VERSION 5.7 ;
  NOWIREEXTENSIONATPIN ON ;
  DIVIDERCHAR "/" ;
  BUSBITCHARS "[]" ;
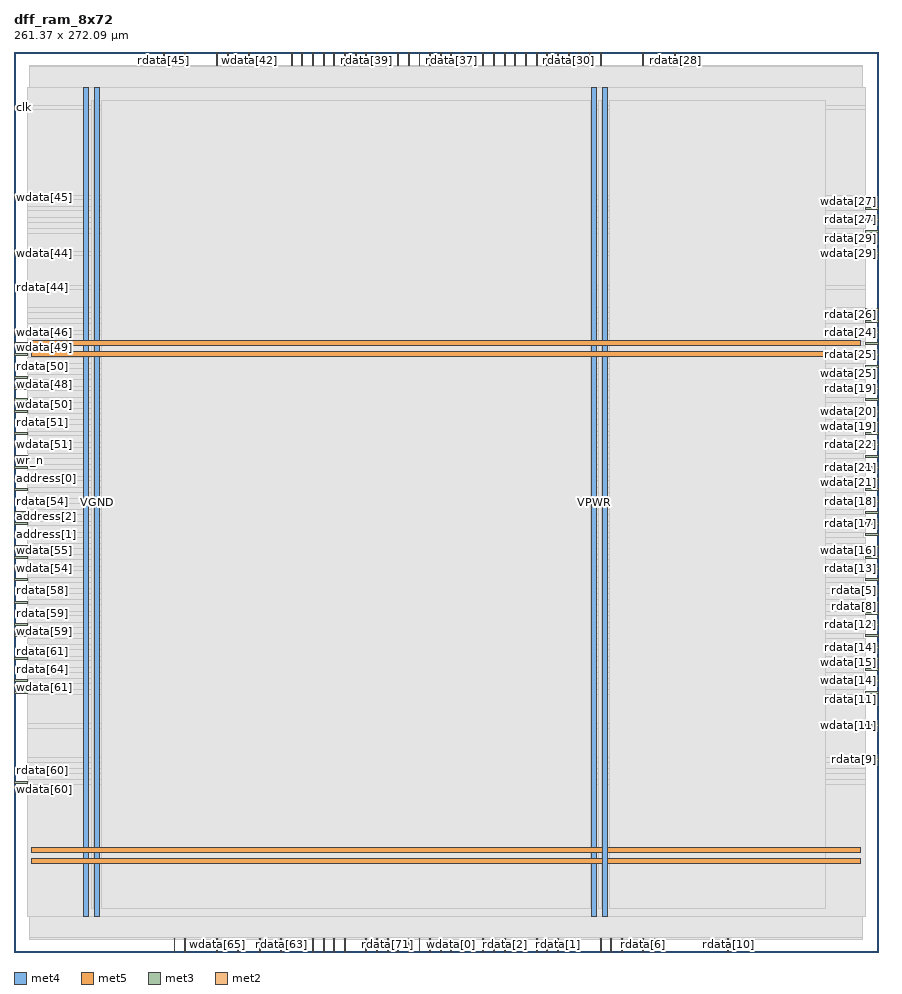
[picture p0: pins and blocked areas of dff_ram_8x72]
MACRO dff_ram_8x72
  CLASS BLOCK ;
  FOREIGN dff_ram_8x72 ;
  ORIGIN 0.000 0.000 ;
  SIZE 261.370 BY 272.090 ;
  PIN VGND
    DIRECTION INOUT ;
    USE GROUND ;
    PORT
      LAYER met4 ;
        RECT 24.340 10.640 25.940 261.360 ;
    END
    PORT
      LAYER met4 ;
        RECT 177.940 10.640 179.540 261.360 ;
    END
    PORT
      LAYER met5 ;
        RECT 5.280 30.030 256.000 31.630 ;
    END
    PORT
      LAYER met5 ;
        RECT 5.280 183.210 256.000 184.810 ;
    END
  END VGND
  PIN VPWR
    DIRECTION INOUT ;
    USE POWER ;
    PORT
      LAYER met4 ;
        RECT 21.040 10.640 22.640 261.360 ;
    END
    PORT
      LAYER met4 ;
        RECT 174.640 10.640 176.240 261.360 ;
    END
    PORT
      LAYER met5 ;
        RECT 5.280 26.730 256.000 28.330 ;
    END
    PORT
      LAYER met5 ;
        RECT 5.280 179.910 256.000 181.510 ;
    END
  END VPWR
  PIN address[0]
    DIRECTION INPUT ;
    USE SIGNAL ;
    ANTENNAGATEAREA 0.126000 ;
    PORT
      LAYER met3 ;
        RECT 0.000 142.840 4.000 143.440 ;
    END
  END address[0]
  PIN address[1]
    DIRECTION INPUT ;
    USE SIGNAL ;
    ANTENNAGATEAREA 0.126000 ;
    PORT
      LAYER met3 ;
        RECT 0.000 125.840 4.000 126.440 ;
    END
  END address[1]
  PIN address[2]
    DIRECTION INPUT ;
    USE SIGNAL ;
    ANTENNAGATEAREA 0.213000 ;
    PORT
      LAYER met3 ;
        RECT 0.000 129.240 4.000 129.840 ;
    END
  END address[2]
  PIN clk
    DIRECTION INPUT ;
    USE SIGNAL ;
    ANTENNAGATEAREA 0.852000 ;
    PORT
      LAYER met3 ;
        RECT 0.000 255.040 4.000 255.640 ;
    END
  END clk
  PIN rdata[0]
    DIRECTION OUTPUT TRISTATE ;
    USE SIGNAL ;
    ANTENNADIFFAREA 0.795200 ;
    PORT
      LAYER met2 ;
        RECT 144.990 0.000 145.270 4.000 ;
    END
  END rdata[0]
  PIN rdata[10]
    DIRECTION OUTPUT TRISTATE ;
    USE SIGNAL ;
    ANTENNADIFFAREA 0.795200 ;
    PORT
      LAYER met2 ;
        RECT 215.830 0.000 216.110 4.000 ;
    END
  END rdata[10]
  PIN rdata[11]
    DIRECTION OUTPUT TRISTATE ;
    USE SIGNAL ;
    ANTENNADIFFAREA 0.795200 ;
    PORT
      LAYER met3 ;
        RECT 257.370 78.240 261.370 78.840 ;
    END
  END rdata[11]
  PIN rdata[12]
    DIRECTION OUTPUT TRISTATE ;
    USE SIGNAL ;
    ANTENNADIFFAREA 0.795200 ;
    PORT
      LAYER met3 ;
        RECT 257.370 98.640 261.370 99.240 ;
    END
  END rdata[12]
  PIN rdata[13]
    DIRECTION OUTPUT TRISTATE ;
    USE SIGNAL ;
    ANTENNADIFFAREA 0.795200 ;
    PORT
      LAYER met3 ;
        RECT 257.370 115.640 261.370 116.240 ;
    END
  END rdata[13]
  PIN rdata[14]
    DIRECTION OUTPUT TRISTATE ;
    USE SIGNAL ;
    ANTENNADIFFAREA 0.795200 ;
    PORT
      LAYER met3 ;
        RECT 257.370 91.840 261.370 92.440 ;
    END
  END rdata[14]
  PIN rdata[15]
    DIRECTION OUTPUT TRISTATE ;
    USE SIGNAL ;
    ANTENNADIFFAREA 0.445500 ;
    PORT
      LAYER met3 ;
        RECT 257.370 95.240 261.370 95.840 ;
    END
  END rdata[15]
  PIN rdata[16]
    DIRECTION OUTPUT TRISTATE ;
    USE SIGNAL ;
    ANTENNADIFFAREA 0.445500 ;
    PORT
      LAYER met3 ;
        RECT 257.370 122.440 261.370 123.040 ;
    END
  END rdata[16]
  PIN rdata[17]
    DIRECTION OUTPUT TRISTATE ;
    USE SIGNAL ;
    ANTENNADIFFAREA 0.445500 ;
    PORT
      LAYER met3 ;
        RECT 257.370 129.240 261.370 129.840 ;
    END
  END rdata[17]
  PIN rdata[18]
    DIRECTION OUTPUT TRISTATE ;
    USE SIGNAL ;
    ANTENNADIFFAREA 0.795200 ;
    PORT
      LAYER met3 ;
        RECT 257.370 136.040 261.370 136.640 ;
    END
  END rdata[18]
  PIN rdata[19]
    DIRECTION OUTPUT TRISTATE ;
    USE SIGNAL ;
    ANTENNADIFFAREA 0.795200 ;
    PORT
      LAYER met3 ;
        RECT 257.370 170.040 261.370 170.640 ;
    END
  END rdata[19]
  PIN rdata[1]
    DIRECTION OUTPUT TRISTATE ;
    USE SIGNAL ;
    ANTENNADIFFAREA 0.795200 ;
    PORT
      LAYER met2 ;
        RECT 164.310 0.000 164.590 4.000 ;
    END
  END rdata[1]
  PIN rdata[20]
    DIRECTION OUTPUT TRISTATE ;
    USE SIGNAL ;
    ANTENNADIFFAREA 0.445500 ;
    PORT
      LAYER met3 ;
        RECT 257.370 166.640 261.370 167.240 ;
    END
  END rdata[20]
  PIN rdata[21]
    DIRECTION OUTPUT TRISTATE ;
    USE SIGNAL ;
    ANTENNADIFFAREA 0.795200 ;
    PORT
      LAYER met3 ;
        RECT 257.370 146.240 261.370 146.840 ;
    END
  END rdata[21]
  PIN rdata[22]
    DIRECTION OUTPUT TRISTATE ;
    USE SIGNAL ;
    ANTENNADIFFAREA 0.795200 ;
    PORT
      LAYER met3 ;
        RECT 257.370 153.040 261.370 153.640 ;
    END
  END rdata[22]
  PIN rdata[23]
    DIRECTION OUTPUT TRISTATE ;
    USE SIGNAL ;
    ANTENNADIFFAREA 0.795200 ;
    PORT
      LAYER met3 ;
        RECT 257.370 149.640 261.370 150.240 ;
    END
  END rdata[23]
  PIN rdata[24]
    DIRECTION OUTPUT TRISTATE ;
    USE SIGNAL ;
    ANTENNADIFFAREA 0.795200 ;
    PORT
      LAYER met3 ;
        RECT 257.370 187.040 261.370 187.640 ;
    END
  END rdata[24]
  PIN rdata[25]
    DIRECTION OUTPUT TRISTATE ;
    USE SIGNAL ;
    ANTENNADIFFAREA 0.795200 ;
    PORT
      LAYER met3 ;
        RECT 257.370 180.240 261.370 180.840 ;
    END
  END rdata[25]
  PIN rdata[26]
    DIRECTION OUTPUT TRISTATE ;
    USE SIGNAL ;
    ANTENNADIFFAREA 0.795200 ;
    PORT
      LAYER met3 ;
        RECT 257.370 190.440 261.370 191.040 ;
    END
  END rdata[26]
  PIN rdata[27]
    DIRECTION OUTPUT TRISTATE ;
    USE SIGNAL ;
    ANTENNADIFFAREA 0.795200 ;
    PORT
      LAYER met3 ;
        RECT 257.370 221.040 261.370 221.640 ;
    END
  END rdata[27]
  PIN rdata[28]
    DIRECTION OUTPUT TRISTATE ;
    USE SIGNAL ;
    ANTENNADIFFAREA 0.795200 ;
    PORT
      LAYER met2 ;
        RECT 199.730 268.090 200.010 272.090 ;
    END
  END rdata[28]
  PIN rdata[29]
    DIRECTION OUTPUT TRISTATE ;
    USE SIGNAL ;
    ANTENNADIFFAREA 0.445500 ;
    PORT
      LAYER met3 ;
        RECT 257.370 217.640 261.370 218.240 ;
    END
  END rdata[29]
  PIN rdata[2]
    DIRECTION OUTPUT TRISTATE ;
    USE SIGNAL ;
    ANTENNADIFFAREA 0.795200 ;
    PORT
      LAYER met2 ;
        RECT 148.210 0.000 148.490 4.000 ;
    END
  END rdata[2]
  PIN rdata[30]
    DIRECTION OUTPUT TRISTATE ;
    USE SIGNAL ;
    ANTENNADIFFAREA 0.795200 ;
    PORT
      LAYER met2 ;
        RECT 167.530 268.090 167.810 272.090 ;
    END
  END rdata[30]
  PIN rdata[31]
    DIRECTION OUTPUT TRISTATE ;
    USE SIGNAL ;
    ANTENNADIFFAREA 0.795200 ;
    PORT
      LAYER met2 ;
        RECT 164.310 268.090 164.590 272.090 ;
    END
  END rdata[31]
  PIN rdata[32]
    DIRECTION OUTPUT TRISTATE ;
    USE SIGNAL ;
    ANTENNADIFFAREA 0.795200 ;
    PORT
      LAYER met2 ;
        RECT 177.190 268.090 177.470 272.090 ;
    END
  END rdata[32]
  PIN rdata[33]
    DIRECTION OUTPUT TRISTATE ;
    USE SIGNAL ;
    ANTENNADIFFAREA 0.795200 ;
    PORT
      LAYER met2 ;
        RECT 161.090 268.090 161.370 272.090 ;
    END
  END rdata[33]
  PIN rdata[34]
    DIRECTION OUTPUT TRISTATE ;
    USE SIGNAL ;
    ANTENNADIFFAREA 0.795200 ;
    PORT
      LAYER met2 ;
        RECT 170.750 268.090 171.030 272.090 ;
    END
  END rdata[34]
  PIN rdata[35]
    DIRECTION OUTPUT TRISTATE ;
    USE SIGNAL ;
    ANTENNADIFFAREA 0.795200 ;
    PORT
      LAYER met2 ;
        RECT 173.970 268.090 174.250 272.090 ;
    END
  END rdata[35]
  PIN rdata[36]
    DIRECTION OUTPUT TRISTATE ;
    USE SIGNAL ;
    ANTENNADIFFAREA 0.795200 ;
    PORT
      LAYER met2 ;
        RECT 135.330 268.090 135.610 272.090 ;
    END
  END rdata[36]
  PIN rdata[37]
    DIRECTION OUTPUT TRISTATE ;
    USE SIGNAL ;
    ANTENNADIFFAREA 0.795200 ;
    PORT
      LAYER met2 ;
        RECT 132.110 268.090 132.390 272.090 ;
    END
  END rdata[37]
  PIN rdata[38]
    DIRECTION OUTPUT TRISTATE ;
    USE SIGNAL ;
    ANTENNADIFFAREA 0.795200 ;
    PORT
      LAYER met2 ;
        RECT 128.890 268.090 129.170 272.090 ;
    END
  END rdata[38]
  PIN rdata[39]
    DIRECTION OUTPUT TRISTATE ;
    USE SIGNAL ;
    ANTENNADIFFAREA 0.795200 ;
    PORT
      LAYER met2 ;
        RECT 106.350 268.090 106.630 272.090 ;
    END
  END rdata[39]
  PIN rdata[3]
    DIRECTION OUTPUT TRISTATE ;
    USE SIGNAL ;
    ANTENNADIFFAREA 0.795200 ;
    PORT
      LAYER met2 ;
        RECT 157.870 0.000 158.150 4.000 ;
    END
  END rdata[3]
  PIN rdata[40]
    DIRECTION OUTPUT TRISTATE ;
    USE SIGNAL ;
    ANTENNADIFFAREA 0.795200 ;
    PORT
      LAYER met2 ;
        RECT 116.010 268.090 116.290 272.090 ;
    END
  END rdata[40]
  PIN rdata[41]
    DIRECTION OUTPUT TRISTATE ;
    USE SIGNAL ;
    ANTENNADIFFAREA 0.795200 ;
    PORT
      LAYER met2 ;
        RECT 103.130 268.090 103.410 272.090 ;
    END
  END rdata[41]
  PIN rdata[42]
    DIRECTION OUTPUT TRISTATE ;
    USE SIGNAL ;
    ANTENNADIFFAREA 0.795200 ;
    PORT
      LAYER met2 ;
        RECT 83.810 268.090 84.090 272.090 ;
    END
  END rdata[42]
  PIN rdata[43]
    DIRECTION OUTPUT TRISTATE ;
    USE SIGNAL ;
    ANTENNADIFFAREA 0.795200 ;
    PORT
      LAYER met2 ;
        RECT 61.270 268.090 61.550 272.090 ;
    END
  END rdata[43]
  PIN rdata[44]
    DIRECTION OUTPUT TRISTATE ;
    USE SIGNAL ;
    ANTENNADIFFAREA 0.795200 ;
    PORT
      LAYER met3 ;
        RECT 0.000 200.640 4.000 201.240 ;
    END
  END rdata[44]
  PIN rdata[45]
    DIRECTION OUTPUT TRISTATE ;
    USE SIGNAL ;
    ANTENNADIFFAREA 0.795200 ;
    PORT
      LAYER met2 ;
        RECT 45.170 268.090 45.450 272.090 ;
    END
  END rdata[45]
  PIN rdata[46]
    DIRECTION OUTPUT TRISTATE ;
    USE SIGNAL ;
    ANTENNADIFFAREA 0.795200 ;
    PORT
      LAYER met2 ;
        RECT 90.250 268.090 90.530 272.090 ;
    END
  END rdata[46]
  PIN rdata[47]
    DIRECTION OUTPUT TRISTATE ;
    USE SIGNAL ;
    ANTENNADIFFAREA 0.795200 ;
    PORT
      LAYER met2 ;
        RECT 87.030 268.090 87.310 272.090 ;
    END
  END rdata[47]
  PIN rdata[48]
    DIRECTION OUTPUT TRISTATE ;
    USE SIGNAL ;
    ANTENNADIFFAREA 0.795200 ;
    PORT
      LAYER met2 ;
        RECT 93.470 268.090 93.750 272.090 ;
    END
  END rdata[48]
  PIN rdata[49]
    DIRECTION OUTPUT TRISTATE ;
    USE SIGNAL ;
    ANTENNADIFFAREA 0.795200 ;
    PORT
      LAYER met3 ;
        RECT 0.000 183.640 4.000 184.240 ;
    END
  END rdata[49]
  PIN rdata[4]
    DIRECTION OUTPUT TRISTATE ;
    USE SIGNAL ;
    ANTENNADIFFAREA 0.795200 ;
    PORT
      LAYER met2 ;
        RECT 161.090 0.000 161.370 4.000 ;
    END
  END rdata[4]
  PIN rdata[50]
    DIRECTION OUTPUT TRISTATE ;
    USE SIGNAL ;
    ANTENNADIFFAREA 0.795200 ;
    PORT
      LAYER met3 ;
        RECT 0.000 176.840 4.000 177.440 ;
    END
  END rdata[50]
  PIN rdata[51]
    DIRECTION OUTPUT TRISTATE ;
    USE SIGNAL ;
    ANTENNADIFFAREA 0.795200 ;
    PORT
      LAYER met3 ;
        RECT 0.000 159.840 4.000 160.440 ;
    END
  END rdata[51]
  PIN rdata[52]
    DIRECTION OUTPUT TRISTATE ;
    USE SIGNAL ;
    ANTENNADIFFAREA 0.795200 ;
    PORT
      LAYER met3 ;
        RECT 0.000 166.640 4.000 167.240 ;
    END
  END rdata[52]
  PIN rdata[53]
    DIRECTION OUTPUT TRISTATE ;
    USE SIGNAL ;
    ANTENNADIFFAREA 0.795200 ;
    PORT
      LAYER met3 ;
        RECT 0.000 149.640 4.000 150.240 ;
    END
  END rdata[53]
  PIN rdata[54]
    DIRECTION OUTPUT TRISTATE ;
    USE SIGNAL ;
    ANTENNADIFFAREA 0.795200 ;
    PORT
      LAYER met3 ;
        RECT 0.000 136.040 4.000 136.640 ;
    END
  END rdata[54]
  PIN rdata[55]
    DIRECTION OUTPUT TRISTATE ;
    USE SIGNAL ;
    ANTENNADIFFAREA 0.795200 ;
    PORT
      LAYER met3 ;
        RECT 0.000 139.440 4.000 140.040 ;
    END
  END rdata[55]
  PIN rdata[56]
    DIRECTION OUTPUT TRISTATE ;
    USE SIGNAL ;
    ANTENNADIFFAREA 0.795200 ;
    PORT
      LAYER met3 ;
        RECT 0.000 132.640 4.000 133.240 ;
    END
  END rdata[56]
  PIN rdata[57]
    DIRECTION OUTPUT TRISTATE ;
    USE SIGNAL ;
    ANTENNADIFFAREA 0.795200 ;
    PORT
      LAYER met3 ;
        RECT 0.000 112.240 4.000 112.840 ;
    END
  END rdata[57]
  PIN rdata[58]
    DIRECTION OUTPUT TRISTATE ;
    USE SIGNAL ;
    ANTENNADIFFAREA 0.795200 ;
    PORT
      LAYER met3 ;
        RECT 0.000 108.840 4.000 109.440 ;
    END
  END rdata[58]
  PIN rdata[59]
    DIRECTION OUTPUT TRISTATE ;
    USE SIGNAL ;
    ANTENNADIFFAREA 0.795200 ;
    PORT
      LAYER met3 ;
        RECT 0.000 102.040 4.000 102.640 ;
    END
  END rdata[59]
  PIN rdata[5]
    DIRECTION OUTPUT TRISTATE ;
    USE SIGNAL ;
    ANTENNADIFFAREA 0.795200 ;
    PORT
      LAYER met3 ;
        RECT 257.370 108.840 261.370 109.440 ;
    END
  END rdata[5]
  PIN rdata[60]
    DIRECTION OUTPUT TRISTATE ;
    USE SIGNAL ;
    ANTENNADIFFAREA 0.795200 ;
    PORT
      LAYER met3 ;
        RECT 0.000 54.440 4.000 55.040 ;
    END
  END rdata[60]
  PIN rdata[61]
    DIRECTION OUTPUT TRISTATE ;
    USE SIGNAL ;
    ANTENNADIFFAREA 0.795200 ;
    PORT
      LAYER met3 ;
        RECT 0.000 88.440 4.000 89.040 ;
    END
  END rdata[61]
  PIN rdata[62]
    DIRECTION OUTPUT TRISTATE ;
    USE SIGNAL ;
    ANTENNADIFFAREA 0.795200 ;
    PORT
      LAYER met2 ;
        RECT 51.610 0.000 51.890 4.000 ;
    END
  END rdata[62]
  PIN rdata[63]
    DIRECTION OUTPUT TRISTATE ;
    USE SIGNAL ;
    ANTENNADIFFAREA 0.795200 ;
    PORT
      LAYER met2 ;
        RECT 80.590 0.000 80.870 4.000 ;
    END
  END rdata[63]
  PIN rdata[64]
    DIRECTION OUTPUT TRISTATE ;
    USE SIGNAL ;
    ANTENNADIFFAREA 0.795200 ;
    PORT
      LAYER met3 ;
        RECT 0.000 85.040 4.000 85.640 ;
    END
  END rdata[64]
  PIN rdata[65]
    DIRECTION OUTPUT TRISTATE ;
    USE SIGNAL ;
    ANTENNADIFFAREA 0.795200 ;
    PORT
      LAYER met2 ;
        RECT 67.710 0.000 67.990 4.000 ;
    END
  END rdata[65]
  PIN rdata[66]
    DIRECTION OUTPUT TRISTATE ;
    USE SIGNAL ;
    ANTENNADIFFAREA 0.795200 ;
    PORT
      LAYER met2 ;
        RECT 99.910 0.000 100.190 4.000 ;
    END
  END rdata[66]
  PIN rdata[67]
    DIRECTION OUTPUT TRISTATE ;
    USE SIGNAL ;
    ANTENNADIFFAREA 0.795200 ;
    PORT
      LAYER met2 ;
        RECT 96.690 0.000 96.970 4.000 ;
    END
  END rdata[67]
  PIN rdata[68]
    DIRECTION OUTPUT TRISTATE ;
    USE SIGNAL ;
    ANTENNADIFFAREA 0.795200 ;
    PORT
      LAYER met2 ;
        RECT 128.890 0.000 129.170 4.000 ;
    END
  END rdata[68]
  PIN rdata[69]
    DIRECTION OUTPUT TRISTATE ;
    USE SIGNAL ;
    ANTENNADIFFAREA 0.795200 ;
    PORT
      LAYER met2 ;
        RECT 122.450 0.000 122.730 4.000 ;
    END
  END rdata[69]
  PIN rdata[6]
    DIRECTION OUTPUT TRISTATE ;
    USE SIGNAL ;
    ANTENNADIFFAREA 0.795200 ;
    PORT
      LAYER met2 ;
        RECT 190.070 0.000 190.350 4.000 ;
    END
  END rdata[6]
  PIN rdata[70]
    DIRECTION OUTPUT TRISTATE ;
    USE SIGNAL ;
    ANTENNADIFFAREA 0.795200 ;
    PORT
      LAYER met2 ;
        RECT 125.670 0.000 125.950 4.000 ;
    END
  END rdata[70]
  PIN rdata[71]
    DIRECTION OUTPUT TRISTATE ;
    USE SIGNAL ;
    ANTENNADIFFAREA 0.795200 ;
    PORT
      LAYER met2 ;
        RECT 112.790 0.000 113.070 4.000 ;
    END
  END rdata[71]
  PIN rdata[7]
    DIRECTION OUTPUT TRISTATE ;
    USE SIGNAL ;
    ANTENNADIFFAREA 0.795200 ;
    PORT
      LAYER met2 ;
        RECT 183.630 0.000 183.910 4.000 ;
    END
  END rdata[7]
  PIN rdata[8]
    DIRECTION OUTPUT TRISTATE ;
    USE SIGNAL ;
    ANTENNADIFFAREA 0.795200 ;
    PORT
      LAYER met3 ;
        RECT 257.370 102.040 261.370 102.640 ;
    END
  END rdata[8]
  PIN rdata[9]
    DIRECTION OUTPUT TRISTATE ;
    USE SIGNAL ;
    ANTENNADIFFAREA 0.445500 ;
    PORT
      LAYER met3 ;
        RECT 257.370 57.840 261.370 58.440 ;
    END
  END rdata[9]
  PIN wdata[0]
    DIRECTION INPUT ;
    USE SIGNAL ;
    ANTENNAGATEAREA 0.196500 ;
    PORT
      LAYER met2 ;
        RECT 132.110 0.000 132.390 4.000 ;
    END
  END wdata[0]
  PIN wdata[10]
    DIRECTION INPUT ;
    USE SIGNAL ;
    ANTENNAGATEAREA 0.196500 ;
    PORT
      LAYER met2 ;
        RECT 196.510 0.000 196.790 4.000 ;
    END
  END wdata[10]
  PIN wdata[11]
    DIRECTION INPUT ;
    USE SIGNAL ;
    ANTENNAGATEAREA 0.196500 ;
    PORT
      LAYER met3 ;
        RECT 257.370 68.040 261.370 68.640 ;
    END
  END wdata[11]
  PIN wdata[12]
    DIRECTION INPUT ;
    USE SIGNAL ;
    ANTENNAGATEAREA 0.196500 ;
    PORT
      LAYER met3 ;
        RECT 257.370 88.440 261.370 89.040 ;
    END
  END wdata[12]
  PIN wdata[13]
    DIRECTION INPUT ;
    USE SIGNAL ;
    ANTENNAGATEAREA 0.196500 ;
    PORT
      LAYER met3 ;
        RECT 257.370 112.240 261.370 112.840 ;
    END
  END wdata[13]
  PIN wdata[14]
    DIRECTION INPUT ;
    USE SIGNAL ;
    ANTENNAGATEAREA 0.196500 ;
    PORT
      LAYER met3 ;
        RECT 257.370 81.640 261.370 82.240 ;
    END
  END wdata[14]
  PIN wdata[15]
    DIRECTION INPUT ;
    USE SIGNAL ;
    ANTENNAGATEAREA 0.196500 ;
    PORT
      LAYER met3 ;
        RECT 257.370 85.040 261.370 85.640 ;
    END
  END wdata[15]
  PIN wdata[16]
    DIRECTION INPUT ;
    USE SIGNAL ;
    ANTENNAGATEAREA 0.196500 ;
    PORT
      LAYER met3 ;
        RECT 257.370 119.040 261.370 119.640 ;
    END
  END wdata[16]
  PIN wdata[17]
    DIRECTION INPUT ;
    USE SIGNAL ;
    ANTENNAGATEAREA 0.196500 ;
    PORT
      LAYER met3 ;
        RECT 257.370 125.840 261.370 126.440 ;
    END
  END wdata[17]
  PIN wdata[18]
    DIRECTION INPUT ;
    USE SIGNAL ;
    ANTENNAGATEAREA 0.196500 ;
    PORT
      LAYER met3 ;
        RECT 257.370 132.640 261.370 133.240 ;
    END
  END wdata[18]
  PIN wdata[19]
    DIRECTION INPUT ;
    USE SIGNAL ;
    ANTENNAGATEAREA 0.196500 ;
    PORT
      LAYER met3 ;
        RECT 257.370 156.440 261.370 157.040 ;
    END
  END wdata[19]
  PIN wdata[1]
    DIRECTION INPUT ;
    USE SIGNAL ;
    ANTENNAGATEAREA 0.196500 ;
    PORT
      LAYER met2 ;
        RECT 154.650 0.000 154.930 4.000 ;
    END
  END wdata[1]
  PIN wdata[20]
    DIRECTION INPUT ;
    USE SIGNAL ;
    ANTENNAGATEAREA 0.126000 ;
    PORT
      LAYER met3 ;
        RECT 257.370 163.240 261.370 163.840 ;
    END
  END wdata[20]
  PIN wdata[21]
    DIRECTION INPUT ;
    USE SIGNAL ;
    ANTENNAGATEAREA 0.196500 ;
    PORT
      LAYER met3 ;
        RECT 257.370 139.440 261.370 140.040 ;
    END
  END wdata[21]
  PIN wdata[22]
    DIRECTION INPUT ;
    USE SIGNAL ;
    ANTENNAGATEAREA 0.196500 ;
    PORT
      LAYER met3 ;
        RECT 257.370 159.840 261.370 160.440 ;
    END
  END wdata[22]
  PIN wdata[23]
    DIRECTION INPUT ;
    USE SIGNAL ;
    ANTENNAGATEAREA 0.126000 ;
    ANTENNADIFFAREA 0.434700 ;
    PORT
      LAYER met3 ;
        RECT 257.370 142.840 261.370 143.440 ;
    END
  END wdata[23]
  PIN wdata[24]
    DIRECTION INPUT ;
    USE SIGNAL ;
    ANTENNAGATEAREA 0.196500 ;
    PORT
      LAYER met3 ;
        RECT 257.370 183.640 261.370 184.240 ;
    END
  END wdata[24]
  PIN wdata[25]
    DIRECTION INPUT ;
    USE SIGNAL ;
    ANTENNAGATEAREA 0.196500 ;
    PORT
      LAYER met3 ;
        RECT 257.370 176.840 261.370 177.440 ;
    END
  END wdata[25]
  PIN wdata[26]
    DIRECTION INPUT ;
    USE SIGNAL ;
    ANTENNAGATEAREA 0.196500 ;
    PORT
      LAYER met3 ;
        RECT 257.370 193.840 261.370 194.440 ;
    END
  END wdata[26]
  PIN wdata[27]
    DIRECTION INPUT ;
    USE SIGNAL ;
    ANTENNAGATEAREA 0.196500 ;
    PORT
      LAYER met3 ;
        RECT 257.370 224.440 261.370 225.040 ;
    END
  END wdata[27]
  PIN wdata[28]
    DIRECTION INPUT ;
    USE SIGNAL ;
    ANTENNAGATEAREA 0.196500 ;
    PORT
      LAYER met2 ;
        RECT 190.070 268.090 190.350 272.090 ;
    END
  END wdata[28]
  PIN wdata[29]
    DIRECTION INPUT ;
    USE SIGNAL ;
    ANTENNAGATEAREA 0.196500 ;
    PORT
      LAYER met3 ;
        RECT 257.370 210.840 261.370 211.440 ;
    END
  END wdata[29]
  PIN wdata[2]
    DIRECTION INPUT ;
    USE SIGNAL ;
    ANTENNAGATEAREA 0.196500 ;
    PORT
      LAYER met2 ;
        RECT 135.330 0.000 135.610 4.000 ;
    END
  END wdata[2]
  PIN wdata[30]
    DIRECTION INPUT ;
    USE SIGNAL ;
    ANTENNAGATEAREA 0.196500 ;
    PORT
      LAYER met2 ;
        RECT 157.870 268.090 158.150 272.090 ;
    END
  END wdata[30]
  PIN wdata[31]
    DIRECTION INPUT ;
    USE SIGNAL ;
    ANTENNAGATEAREA 0.126000 ;
    PORT
      LAYER met2 ;
        RECT 141.770 268.090 142.050 272.090 ;
    END
  END wdata[31]
  PIN wdata[32]
    DIRECTION INPUT ;
    USE SIGNAL ;
    ANTENNAGATEAREA 0.196500 ;
    PORT
      LAYER met2 ;
        RECT 148.210 268.090 148.490 272.090 ;
    END
  END wdata[32]
  PIN wdata[33]
    DIRECTION INPUT ;
    USE SIGNAL ;
    ANTENNAGATEAREA 0.196500 ;
    PORT
      LAYER met2 ;
        RECT 154.650 268.090 154.930 272.090 ;
    END
  END wdata[33]
  PIN wdata[34]
    DIRECTION INPUT ;
    USE SIGNAL ;
    ANTENNAGATEAREA 0.196500 ;
    PORT
      LAYER met2 ;
        RECT 144.990 268.090 145.270 272.090 ;
    END
  END wdata[34]
  PIN wdata[35]
    DIRECTION INPUT ;
    USE SIGNAL ;
    ANTENNAGATEAREA 0.196500 ;
    PORT
      LAYER met2 ;
        RECT 151.430 268.090 151.710 272.090 ;
    END
  END wdata[35]
  PIN wdata[36]
    DIRECTION INPUT ;
    USE SIGNAL ;
    ANTENNAGATEAREA 0.196500 ;
    PORT
      LAYER met2 ;
        RECT 125.670 268.090 125.950 272.090 ;
    END
  END wdata[36]
  PIN wdata[37]
    DIRECTION INPUT ;
    USE SIGNAL ;
    ANTENNAGATEAREA 0.196500 ;
    PORT
      LAYER met2 ;
        RECT 119.230 268.090 119.510 272.090 ;
    END
  END wdata[37]
  PIN wdata[38]
    DIRECTION INPUT ;
    USE SIGNAL ;
    ANTENNAGATEAREA 0.196500 ;
    PORT
      LAYER met2 ;
        RECT 122.450 268.090 122.730 272.090 ;
    END
  END wdata[38]
  PIN wdata[39]
    DIRECTION INPUT ;
    USE SIGNAL ;
    ANTENNAGATEAREA 0.196500 ;
    PORT
      LAYER met2 ;
        RECT 96.690 268.090 96.970 272.090 ;
    END
  END wdata[39]
  PIN wdata[3]
    DIRECTION INPUT ;
    USE SIGNAL ;
    ANTENNAGATEAREA 0.196500 ;
    PORT
      LAYER met2 ;
        RECT 141.770 0.000 142.050 4.000 ;
    END
  END wdata[3]
  PIN wdata[40]
    DIRECTION INPUT ;
    USE SIGNAL ;
    ANTENNAGATEAREA 0.196500 ;
    PORT
      LAYER met2 ;
        RECT 109.570 268.090 109.850 272.090 ;
    END
  END wdata[40]
  PIN wdata[41]
    DIRECTION INPUT ;
    USE SIGNAL ;
    ANTENNAGATEAREA 0.196500 ;
    PORT
      LAYER met2 ;
        RECT 99.910 268.090 100.190 272.090 ;
    END
  END wdata[41]
  PIN wdata[42]
    DIRECTION INPUT ;
    USE SIGNAL ;
    ANTENNAGATEAREA 0.196500 ;
    PORT
      LAYER met2 ;
        RECT 70.930 268.090 71.210 272.090 ;
    END
  END wdata[42]
  PIN wdata[43]
    DIRECTION INPUT ;
    USE SIGNAL ;
    ANTENNAGATEAREA 0.196500 ;
    PORT
      LAYER met2 ;
        RECT 51.610 268.090 51.890 272.090 ;
    END
  END wdata[43]
  PIN wdata[44]
    DIRECTION INPUT ;
    USE SIGNAL ;
    ANTENNAGATEAREA 0.196500 ;
    PORT
      LAYER met3 ;
        RECT 0.000 210.840 4.000 211.440 ;
    END
  END wdata[44]
  PIN wdata[45]
    DIRECTION INPUT ;
    USE SIGNAL ;
    ANTENNAGATEAREA 0.196500 ;
    PORT
      LAYER met3 ;
        RECT 0.000 227.840 4.000 228.440 ;
    END
  END wdata[45]
  PIN wdata[46]
    DIRECTION INPUT ;
    USE SIGNAL ;
    ANTENNAGATEAREA 0.196500 ;
    PORT
      LAYER met3 ;
        RECT 0.000 187.040 4.000 187.640 ;
    END
  END wdata[46]
  PIN wdata[47]
    DIRECTION INPUT ;
    USE SIGNAL ;
    ANTENNAGATEAREA 0.196500 ;
    PORT
      LAYER met2 ;
        RECT 64.490 268.090 64.770 272.090 ;
    END
  END wdata[47]
  PIN wdata[48]
    DIRECTION INPUT ;
    USE SIGNAL ;
    ANTENNAGATEAREA 0.196500 ;
    PORT
      LAYER met3 ;
        RECT 0.000 173.440 4.000 174.040 ;
    END
  END wdata[48]
  PIN wdata[49]
    DIRECTION INPUT ;
    USE SIGNAL ;
    ANTENNAGATEAREA 0.196500 ;
    PORT
      LAYER met3 ;
        RECT 0.000 180.240 4.000 180.840 ;
    END
  END wdata[49]
  PIN wdata[4]
    DIRECTION INPUT ;
    USE SIGNAL ;
    ANTENNAGATEAREA 0.196500 ;
    PORT
      LAYER met2 ;
        RECT 138.550 0.000 138.830 4.000 ;
    END
  END wdata[4]
  PIN wdata[50]
    DIRECTION INPUT ;
    USE SIGNAL ;
    ANTENNAGATEAREA 0.196500 ;
    PORT
      LAYER met3 ;
        RECT 0.000 163.240 4.000 163.840 ;
    END
  END wdata[50]
  PIN wdata[51]
    DIRECTION INPUT ;
    USE SIGNAL ;
    ANTENNAGATEAREA 0.196500 ;
    PORT
      LAYER met3 ;
        RECT 0.000 153.040 4.000 153.640 ;
    END
  END wdata[51]
  PIN wdata[52]
    DIRECTION INPUT ;
    USE SIGNAL ;
    ANTENNAGATEAREA 0.196500 ;
    PORT
      LAYER met3 ;
        RECT 0.000 170.040 4.000 170.640 ;
    END
  END wdata[52]
  PIN wdata[53]
    DIRECTION INPUT ;
    USE SIGNAL ;
    ANTENNAGATEAREA 0.196500 ;
    PORT
      LAYER met3 ;
        RECT 0.000 156.440 4.000 157.040 ;
    END
  END wdata[53]
  PIN wdata[54]
    DIRECTION INPUT ;
    USE SIGNAL ;
    ANTENNAGATEAREA 0.196500 ;
    PORT
      LAYER met3 ;
        RECT 0.000 115.640 4.000 116.240 ;
    END
  END wdata[54]
  PIN wdata[55]
    DIRECTION INPUT ;
    USE SIGNAL ;
    ANTENNAGATEAREA 0.196500 ;
    PORT
      LAYER met3 ;
        RECT 0.000 119.040 4.000 119.640 ;
    END
  END wdata[55]
  PIN wdata[56]
    DIRECTION INPUT ;
    USE SIGNAL ;
    ANTENNAGATEAREA 0.196500 ;
    PORT
      LAYER met3 ;
        RECT 0.000 122.440 4.000 123.040 ;
    END
  END wdata[56]
  PIN wdata[57]
    DIRECTION INPUT ;
    USE SIGNAL ;
    ANTENNAGATEAREA 0.196500 ;
    PORT
      LAYER met3 ;
        RECT 0.000 105.440 4.000 106.040 ;
    END
  END wdata[57]
  PIN wdata[58]
    DIRECTION INPUT ;
    USE SIGNAL ;
    ANTENNAGATEAREA 0.196500 ;
    PORT
      LAYER met3 ;
        RECT 0.000 95.240 4.000 95.840 ;
    END
  END wdata[58]
  PIN wdata[59]
    DIRECTION INPUT ;
    USE SIGNAL ;
    ANTENNAGATEAREA 0.196500 ;
    PORT
      LAYER met3 ;
        RECT 0.000 98.640 4.000 99.240 ;
    END
  END wdata[59]
  PIN wdata[5]
    DIRECTION INPUT ;
    USE SIGNAL ;
    ANTENNAGATEAREA 0.196500 ;
    PORT
      LAYER met2 ;
        RECT 151.430 0.000 151.710 4.000 ;
    END
  END wdata[5]
  PIN wdata[60]
    DIRECTION INPUT ;
    USE SIGNAL ;
    ANTENNAGATEAREA 0.196500 ;
    PORT
      LAYER met3 ;
        RECT 0.000 51.040 4.000 51.640 ;
    END
  END wdata[60]
  PIN wdata[61]
    DIRECTION INPUT ;
    USE SIGNAL ;
    ANTENNAGATEAREA 0.196500 ;
    PORT
      LAYER met3 ;
        RECT 0.000 81.640 4.000 82.240 ;
    END
  END wdata[61]
  PIN wdata[62]
    DIRECTION INPUT ;
    USE SIGNAL ;
    ANTENNAGATEAREA 0.196500 ;
    PORT
      LAYER met2 ;
        RECT 48.390 0.000 48.670 4.000 ;
    END
  END wdata[62]
  PIN wdata[63]
    DIRECTION INPUT ;
    USE SIGNAL ;
    ANTENNAGATEAREA 0.196500 ;
    PORT
      LAYER met2 ;
        RECT 74.150 0.000 74.430 4.000 ;
    END
  END wdata[63]
  PIN wdata[64]
    DIRECTION INPUT ;
    USE SIGNAL ;
    ANTENNAGATEAREA 0.196500 ;
    PORT
      LAYER met3 ;
        RECT 0.000 78.240 4.000 78.840 ;
    END
  END wdata[64]
  PIN wdata[65]
    DIRECTION INPUT ;
    USE SIGNAL ;
    ANTENNAGATEAREA 0.196500 ;
    PORT
      LAYER met2 ;
        RECT 61.270 0.000 61.550 4.000 ;
    END
  END wdata[65]
  PIN wdata[66]
    DIRECTION INPUT ;
    USE SIGNAL ;
    ANTENNAGATEAREA 0.196500 ;
    PORT
      LAYER met2 ;
        RECT 93.470 0.000 93.750 4.000 ;
    END
  END wdata[66]
  PIN wdata[67]
    DIRECTION INPUT ;
    USE SIGNAL ;
    ANTENNAGATEAREA 0.196500 ;
    PORT
      LAYER met2 ;
        RECT 90.250 0.000 90.530 4.000 ;
    END
  END wdata[67]
  PIN wdata[68]
    DIRECTION INPUT ;
    USE SIGNAL ;
    ANTENNAGATEAREA 0.196500 ;
    PORT
      LAYER met2 ;
        RECT 116.010 0.000 116.290 4.000 ;
    END
  END wdata[68]
  PIN wdata[69]
    DIRECTION INPUT ;
    USE SIGNAL ;
    ANTENNAGATEAREA 0.196500 ;
    PORT
      LAYER met2 ;
        RECT 119.230 0.000 119.510 4.000 ;
    END
  END wdata[69]
  PIN wdata[6]
    DIRECTION INPUT ;
    USE SIGNAL ;
    ANTENNAGATEAREA 0.196500 ;
    PORT
      LAYER met2 ;
        RECT 180.410 0.000 180.690 4.000 ;
    END
  END wdata[6]
  PIN wdata[70]
    DIRECTION INPUT ;
    USE SIGNAL ;
    ANTENNAGATEAREA 0.196500 ;
    PORT
      LAYER met2 ;
        RECT 109.570 0.000 109.850 4.000 ;
    END
  END wdata[70]
  PIN wdata[71]
    DIRECTION INPUT ;
    USE SIGNAL ;
    ANTENNAGATEAREA 0.196500 ;
    PORT
      LAYER met2 ;
        RECT 106.350 0.000 106.630 4.000 ;
    END
  END wdata[71]
  PIN wdata[7]
    DIRECTION INPUT ;
    USE SIGNAL ;
    ANTENNAGATEAREA 0.196500 ;
    PORT
      LAYER met2 ;
        RECT 177.190 0.000 177.470 4.000 ;
    END
  END wdata[7]
  PIN wdata[8]
    DIRECTION INPUT ;
    USE SIGNAL ;
    ANTENNAGATEAREA 0.196500 ;
    PORT
      LAYER met3 ;
        RECT 257.370 105.440 261.370 106.040 ;
    END
  END wdata[8]
  PIN wdata[9]
    DIRECTION INPUT ;
    USE SIGNAL ;
    ANTENNAGATEAREA 0.196500 ;
    PORT
      LAYER met2 ;
        RECT 193.290 0.000 193.570 4.000 ;
    END
  END wdata[9]
  PIN wr_n
    DIRECTION INPUT ;
    USE SIGNAL ;
    ANTENNAGATEAREA 0.196500 ;
    PORT
      LAYER met3 ;
        RECT 0.000 146.240 4.000 146.840 ;
    END
  END wr_n
  OBS
      LAYER li1 ;
        RECT 5.520 10.795 255.760 261.205 ;
      LAYER met1 ;
        RECT 4.670 9.900 256.610 261.360 ;
      LAYER met2 ;
        RECT 4.690 267.810 44.890 268.090 ;
        RECT 45.730 267.810 51.330 268.090 ;
        RECT 52.170 267.810 60.990 268.090 ;
        RECT 61.830 267.810 64.210 268.090 ;
        RECT 65.050 267.810 70.650 268.090 ;
        RECT 71.490 267.810 83.530 268.090 ;
        RECT 84.370 267.810 86.750 268.090 ;
        RECT 87.590 267.810 89.970 268.090 ;
        RECT 90.810 267.810 93.190 268.090 ;
        RECT 94.030 267.810 96.410 268.090 ;
        RECT 97.250 267.810 99.630 268.090 ;
        RECT 100.470 267.810 102.850 268.090 ;
        RECT 103.690 267.810 106.070 268.090 ;
        RECT 106.910 267.810 109.290 268.090 ;
        RECT 110.130 267.810 115.730 268.090 ;
        RECT 116.570 267.810 118.950 268.090 ;
        RECT 119.790 267.810 122.170 268.090 ;
        RECT 123.010 267.810 125.390 268.090 ;
        RECT 126.230 267.810 128.610 268.090 ;
        RECT 129.450 267.810 131.830 268.090 ;
        RECT 132.670 267.810 135.050 268.090 ;
        RECT 135.890 267.810 141.490 268.090 ;
        RECT 142.330 267.810 144.710 268.090 ;
        RECT 145.550 267.810 147.930 268.090 ;
        RECT 148.770 267.810 151.150 268.090 ;
        RECT 151.990 267.810 154.370 268.090 ;
        RECT 155.210 267.810 157.590 268.090 ;
        RECT 158.430 267.810 160.810 268.090 ;
        RECT 161.650 267.810 164.030 268.090 ;
        RECT 164.870 267.810 167.250 268.090 ;
        RECT 168.090 267.810 170.470 268.090 ;
        RECT 171.310 267.810 173.690 268.090 ;
        RECT 174.530 267.810 176.910 268.090 ;
        RECT 177.750 267.810 189.790 268.090 ;
        RECT 190.630 267.810 199.450 268.090 ;
        RECT 200.290 267.810 256.590 268.090 ;
        RECT 4.690 4.280 256.590 267.810 ;
        RECT 4.690 3.670 48.110 4.280 ;
        RECT 48.950 3.670 51.330 4.280 ;
        RECT 52.170 3.670 60.990 4.280 ;
        RECT 61.830 3.670 67.430 4.280 ;
        RECT 68.270 3.670 73.870 4.280 ;
        RECT 74.710 3.670 80.310 4.280 ;
        RECT 81.150 3.670 89.970 4.280 ;
        RECT 90.810 3.670 93.190 4.280 ;
        RECT 94.030 3.670 96.410 4.280 ;
        RECT 97.250 3.670 99.630 4.280 ;
        RECT 100.470 3.670 106.070 4.280 ;
        RECT 106.910 3.670 109.290 4.280 ;
        RECT 110.130 3.670 112.510 4.280 ;
        RECT 113.350 3.670 115.730 4.280 ;
        RECT 116.570 3.670 118.950 4.280 ;
        RECT 119.790 3.670 122.170 4.280 ;
        RECT 123.010 3.670 125.390 4.280 ;
        RECT 126.230 3.670 128.610 4.280 ;
        RECT 129.450 3.670 131.830 4.280 ;
        RECT 132.670 3.670 135.050 4.280 ;
        RECT 135.890 3.670 138.270 4.280 ;
        RECT 139.110 3.670 141.490 4.280 ;
        RECT 142.330 3.670 144.710 4.280 ;
        RECT 145.550 3.670 147.930 4.280 ;
        RECT 148.770 3.670 151.150 4.280 ;
        RECT 151.990 3.670 154.370 4.280 ;
        RECT 155.210 3.670 157.590 4.280 ;
        RECT 158.430 3.670 160.810 4.280 ;
        RECT 161.650 3.670 164.030 4.280 ;
        RECT 164.870 3.670 176.910 4.280 ;
        RECT 177.750 3.670 180.130 4.280 ;
        RECT 180.970 3.670 183.350 4.280 ;
        RECT 184.190 3.670 189.790 4.280 ;
        RECT 190.630 3.670 193.010 4.280 ;
        RECT 193.850 3.670 196.230 4.280 ;
        RECT 197.070 3.670 215.550 4.280 ;
        RECT 216.390 3.670 256.590 4.280 ;
      LAYER met3 ;
        RECT 3.990 256.040 257.370 261.285 ;
        RECT 4.400 254.640 257.370 256.040 ;
        RECT 3.990 228.840 257.370 254.640 ;
        RECT 4.400 227.440 257.370 228.840 ;
        RECT 3.990 225.440 257.370 227.440 ;
        RECT 3.990 224.040 256.970 225.440 ;
        RECT 3.990 222.040 257.370 224.040 ;
        RECT 3.990 220.640 256.970 222.040 ;
        RECT 3.990 218.640 257.370 220.640 ;
        RECT 3.990 217.240 256.970 218.640 ;
        RECT 3.990 211.840 257.370 217.240 ;
        RECT 4.400 210.440 256.970 211.840 ;
        RECT 3.990 201.640 257.370 210.440 ;
        RECT 4.400 200.240 257.370 201.640 ;
        RECT 3.990 194.840 257.370 200.240 ;
        RECT 3.990 193.440 256.970 194.840 ;
        RECT 3.990 191.440 257.370 193.440 ;
        RECT 3.990 190.040 256.970 191.440 ;
        RECT 3.990 188.040 257.370 190.040 ;
        RECT 4.400 186.640 256.970 188.040 ;
        RECT 3.990 184.640 257.370 186.640 ;
        RECT 4.400 183.240 256.970 184.640 ;
        RECT 3.990 181.240 257.370 183.240 ;
        RECT 4.400 179.840 256.970 181.240 ;
        RECT 3.990 177.840 257.370 179.840 ;
        RECT 4.400 176.440 256.970 177.840 ;
        RECT 3.990 174.440 257.370 176.440 ;
        RECT 4.400 173.040 257.370 174.440 ;
        RECT 3.990 171.040 257.370 173.040 ;
        RECT 4.400 169.640 256.970 171.040 ;
        RECT 3.990 167.640 257.370 169.640 ;
        RECT 4.400 166.240 256.970 167.640 ;
        RECT 3.990 164.240 257.370 166.240 ;
        RECT 4.400 162.840 256.970 164.240 ;
        RECT 3.990 160.840 257.370 162.840 ;
        RECT 4.400 159.440 256.970 160.840 ;
        RECT 3.990 157.440 257.370 159.440 ;
        RECT 4.400 156.040 256.970 157.440 ;
        RECT 3.990 154.040 257.370 156.040 ;
        RECT 4.400 152.640 256.970 154.040 ;
        RECT 3.990 150.640 257.370 152.640 ;
        RECT 4.400 149.240 256.970 150.640 ;
        RECT 3.990 147.240 257.370 149.240 ;
        RECT 4.400 145.840 256.970 147.240 ;
        RECT 3.990 143.840 257.370 145.840 ;
        RECT 4.400 142.440 256.970 143.840 ;
        RECT 3.990 140.440 257.370 142.440 ;
        RECT 4.400 139.040 256.970 140.440 ;
        RECT 3.990 137.040 257.370 139.040 ;
        RECT 4.400 135.640 256.970 137.040 ;
        RECT 3.990 133.640 257.370 135.640 ;
        RECT 4.400 132.240 256.970 133.640 ;
        RECT 3.990 130.240 257.370 132.240 ;
        RECT 4.400 128.840 256.970 130.240 ;
        RECT 3.990 126.840 257.370 128.840 ;
        RECT 4.400 125.440 256.970 126.840 ;
        RECT 3.990 123.440 257.370 125.440 ;
        RECT 4.400 122.040 256.970 123.440 ;
        RECT 3.990 120.040 257.370 122.040 ;
        RECT 4.400 118.640 256.970 120.040 ;
        RECT 3.990 116.640 257.370 118.640 ;
        RECT 4.400 115.240 256.970 116.640 ;
        RECT 3.990 113.240 257.370 115.240 ;
        RECT 4.400 111.840 256.970 113.240 ;
        RECT 3.990 109.840 257.370 111.840 ;
        RECT 4.400 108.440 256.970 109.840 ;
        RECT 3.990 106.440 257.370 108.440 ;
        RECT 4.400 105.040 256.970 106.440 ;
        RECT 3.990 103.040 257.370 105.040 ;
        RECT 4.400 101.640 256.970 103.040 ;
        RECT 3.990 99.640 257.370 101.640 ;
        RECT 4.400 98.240 256.970 99.640 ;
        RECT 3.990 96.240 257.370 98.240 ;
        RECT 4.400 94.840 256.970 96.240 ;
        RECT 3.990 92.840 257.370 94.840 ;
        RECT 3.990 91.440 256.970 92.840 ;
        RECT 3.990 89.440 257.370 91.440 ;
        RECT 4.400 88.040 256.970 89.440 ;
        RECT 3.990 86.040 257.370 88.040 ;
        RECT 4.400 84.640 256.970 86.040 ;
        RECT 3.990 82.640 257.370 84.640 ;
        RECT 4.400 81.240 256.970 82.640 ;
        RECT 3.990 79.240 257.370 81.240 ;
        RECT 4.400 77.840 256.970 79.240 ;
        RECT 3.990 69.040 257.370 77.840 ;
        RECT 3.990 67.640 256.970 69.040 ;
        RECT 3.990 58.840 257.370 67.640 ;
        RECT 3.990 57.440 256.970 58.840 ;
        RECT 3.990 55.440 257.370 57.440 ;
        RECT 4.400 54.040 257.370 55.440 ;
        RECT 3.990 52.040 257.370 54.040 ;
        RECT 4.400 50.640 257.370 52.040 ;
        RECT 3.990 10.715 257.370 50.640 ;
      LAYER met4 ;
        RECT 23.295 13.095 23.940 257.545 ;
        RECT 26.340 13.095 174.240 257.545 ;
        RECT 176.640 13.095 177.540 257.545 ;
        RECT 179.940 13.095 245.345 257.545 ;
  END
END dff_ram_8x72
END LIBRARY

